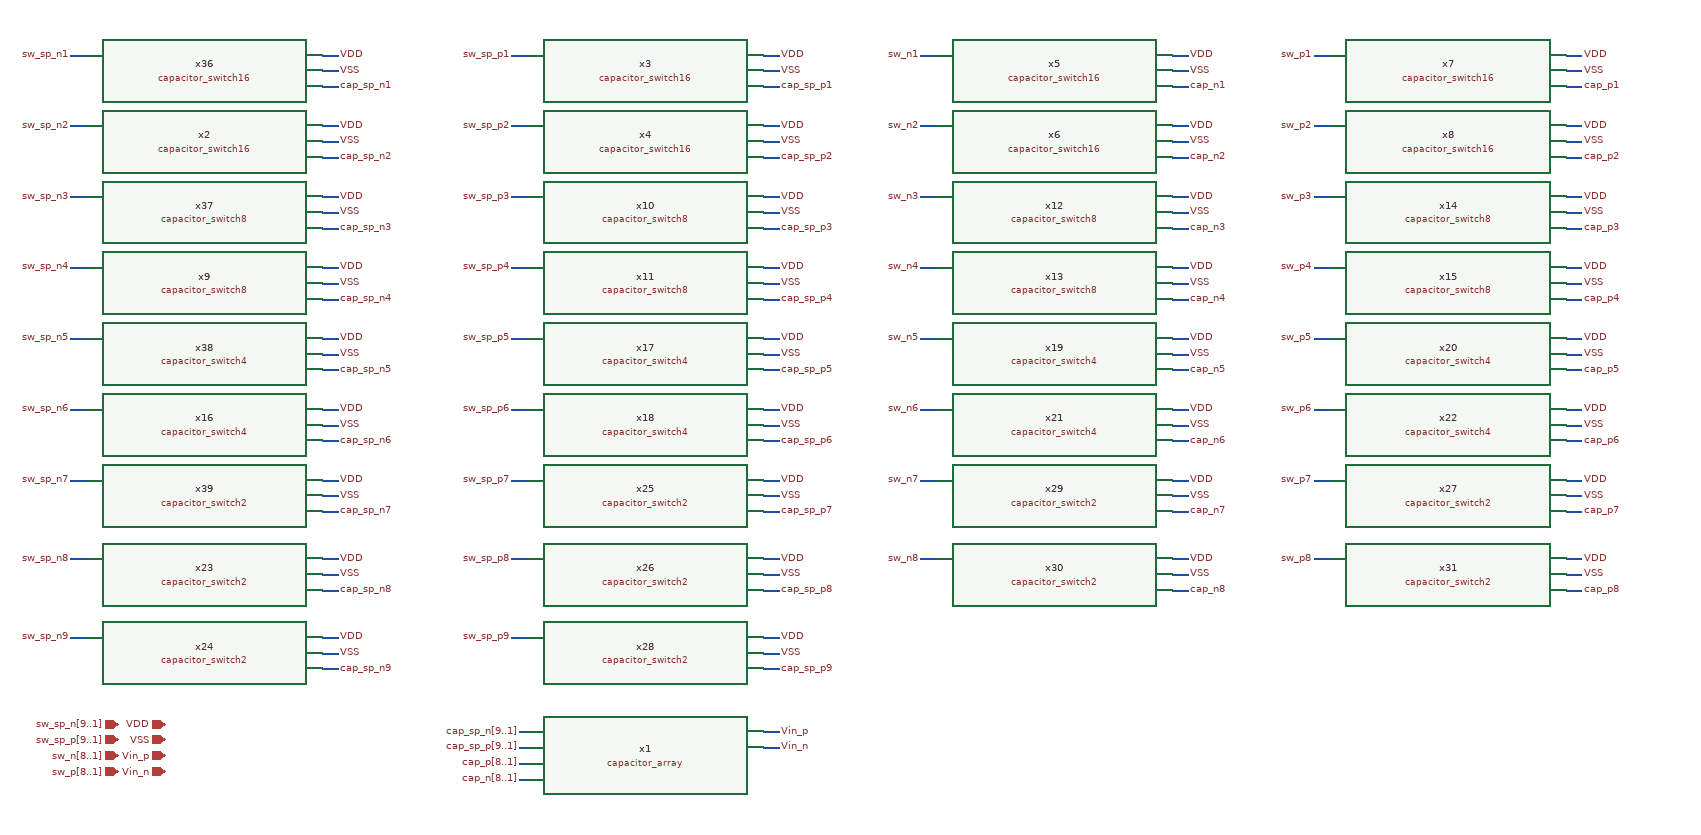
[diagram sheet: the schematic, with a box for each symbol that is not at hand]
v {xschem version=3.1.0 file_version=1.2
}
G {}
K {}
V {}
S {}
E {}
N 690 -110 700 -110 {
lab=cap_sp_n[9..1]}
N 690 -90 700 -90 {
lab=cap_sp_p[9..1]}
N 690 -70 700 -70 {
lab=cap_p[8..1]}
N 690 -50 700 -50 {
lab=cap_n[8..1]}
N 1000 -110 1020 -110 {
lab=Vin_p}
N 1000 -90 1020 -90 {
lab=Vin_n}
N 440 -930 460 -930 {
lab=cap_sp_n1}
N 440 -970 460 -970 {
lab=VDD}
N 440 -950 460 -950 {
lab=VSS}
N 120 -970 140 -970 {
lab=sw_sp_n1}
N 440 -840 460 -840 {
lab=cap_sp_n2}
N 440 -880 460 -880 {
lab=VDD}
N 440 -860 460 -860 {
lab=VSS}
N 120 -880 140 -880 {
lab=sw_sp_n2}
N 440 -750 460 -750 {
lab=cap_sp_n3}
N 440 -790 460 -790 {
lab=VDD}
N 440 -770 460 -770 {
lab=VSS}
N 120 -790 140 -790 {
lab=sw_sp_n3}
N 440 -660 460 -660 {
lab=cap_sp_n4}
N 440 -700 460 -700 {
lab=VDD}
N 440 -680 460 -680 {
lab=VSS}
N 120 -700 140 -700 {
lab=sw_sp_n4}
N 440 -570 460 -570 {
lab=cap_sp_n5}
N 440 -610 460 -610 {
lab=VDD}
N 440 -590 460 -590 {
lab=VSS}
N 120 -610 140 -610 {
lab=sw_sp_n5}
N 440 -480 460 -480 {
lab=cap_sp_n6}
N 440 -520 460 -520 {
lab=VDD}
N 440 -500 460 -500 {
lab=VSS}
N 120 -520 140 -520 {
lab=sw_sp_n6}
N 440 -390 460 -390 {
lab=cap_sp_n7}
N 440 -430 460 -430 {
lab=VDD}
N 440 -410 460 -410 {
lab=VSS}
N 120 -430 140 -430 {
lab=sw_sp_n7}
N 440 -290 460 -290 {
lab=cap_sp_n8}
N 440 -330 460 -330 {
lab=VDD}
N 440 -310 460 -310 {
lab=VSS}
N 120 -330 140 -330 {
lab=sw_sp_n8}
N 440 -190 460 -190 {
lab=cap_sp_n9}
N 440 -230 460 -230 {
lab=VDD}
N 440 -210 460 -210 {
lab=VSS}
N 120 -230 140 -230 {
lab=sw_sp_n9}
N 1000 -930 1020 -930 {
lab=cap_sp_p1}
N 1000 -970 1020 -970 {
lab=VDD}
N 1000 -950 1020 -950 {
lab=VSS}
N 680 -970 700 -970 {
lab=sw_sp_p1}
N 1000 -840 1020 -840 {
lab=cap_sp_p2}
N 1000 -880 1020 -880 {
lab=VDD}
N 1000 -860 1020 -860 {
lab=VSS}
N 680 -880 700 -880 {
lab=sw_sp_p2}
N 1000 -750 1020 -750 {
lab=cap_sp_p3}
N 1000 -790 1020 -790 {
lab=VDD}
N 1000 -770 1020 -770 {
lab=VSS}
N 680 -790 700 -790 {
lab=sw_sp_p3}
N 1000 -660 1020 -660 {
lab=cap_sp_p4}
N 1000 -700 1020 -700 {
lab=VDD}
N 1000 -680 1020 -680 {
lab=VSS}
N 680 -700 700 -700 {
lab=sw_sp_p4}
N 1000 -570 1020 -570 {
lab=cap_sp_p5}
N 1000 -610 1020 -610 {
lab=VDD}
N 1000 -590 1020 -590 {
lab=VSS}
N 680 -610 700 -610 {
lab=sw_sp_p5}
N 1000 -480 1020 -480 {
lab=cap_sp_p6}
N 1000 -520 1020 -520 {
lab=VDD}
N 1000 -500 1020 -500 {
lab=VSS}
N 680 -520 700 -520 {
lab=sw_sp_p6}
N 1000 -390 1020 -390 {
lab=cap_sp_p7}
N 1000 -430 1020 -430 {
lab=VDD}
N 1000 -410 1020 -410 {
lab=VSS}
N 680 -430 700 -430 {
lab=sw_sp_p7}
N 1000 -290 1020 -290 {
lab=cap_sp_p8}
N 1000 -330 1020 -330 {
lab=VDD}
N 1000 -310 1020 -310 {
lab=VSS}
N 680 -330 700 -330 {
lab=sw_sp_p8}
N 1000 -190 1020 -190 {
lab=cap_sp_p9}
N 1000 -230 1020 -230 {
lab=VDD}
N 1000 -210 1020 -210 {
lab=VSS}
N 680 -230 700 -230 {
lab=sw_sp_p9}
N 2020 -930 2040 -930 {
lab=cap_p1}
N 2020 -970 2040 -970 {
lab=VDD}
N 2020 -950 2040 -950 {
lab=VSS}
N 1700 -970 1720 -970 {
lab=sw_p1}
N 2020 -840 2040 -840 {
lab=cap_p2}
N 2020 -880 2040 -880 {
lab=VDD}
N 2020 -860 2040 -860 {
lab=VSS}
N 1700 -880 1720 -880 {
lab=sw_p2}
N 2020 -750 2040 -750 {
lab=cap_p3}
N 2020 -790 2040 -790 {
lab=VDD}
N 2020 -770 2040 -770 {
lab=VSS}
N 1700 -790 1720 -790 {
lab=sw_p3}
N 2020 -660 2040 -660 {
lab=cap_p4}
N 2020 -700 2040 -700 {
lab=VDD}
N 2020 -680 2040 -680 {
lab=VSS}
N 1700 -700 1720 -700 {
lab=sw_p4}
N 2020 -570 2040 -570 {
lab=cap_p5}
N 2020 -610 2040 -610 {
lab=VDD}
N 2020 -590 2040 -590 {
lab=VSS}
N 1700 -610 1720 -610 {
lab=sw_p5}
N 2020 -480 2040 -480 {
lab=cap_p6}
N 2020 -520 2040 -520 {
lab=VDD}
N 2020 -500 2040 -500 {
lab=VSS}
N 1700 -520 1720 -520 {
lab=sw_p6}
N 2020 -390 2040 -390 {
lab=cap_p7}
N 2020 -430 2040 -430 {
lab=VDD}
N 2020 -410 2040 -410 {
lab=VSS}
N 1700 -430 1720 -430 {
lab=sw_p7}
N 2020 -290 2040 -290 {
lab=cap_p8}
N 2020 -330 2040 -330 {
lab=VDD}
N 2020 -310 2040 -310 {
lab=VSS}
N 1700 -330 1720 -330 {
lab=sw_p8}
N 1520 -930 1540 -930 {
lab=cap_n1}
N 1520 -970 1540 -970 {
lab=VDD}
N 1520 -950 1540 -950 {
lab=VSS}
N 1200 -970 1220 -970 {
lab=sw_n1}
N 1520 -840 1540 -840 {
lab=cap_n2}
N 1520 -880 1540 -880 {
lab=VDD}
N 1520 -860 1540 -860 {
lab=VSS}
N 1200 -880 1220 -880 {
lab=sw_n2}
N 1520 -750 1540 -750 {
lab=cap_n3}
N 1520 -790 1540 -790 {
lab=VDD}
N 1520 -770 1540 -770 {
lab=VSS}
N 1200 -790 1220 -790 {
lab=sw_n3}
N 1520 -660 1540 -660 {
lab=cap_n4}
N 1520 -700 1540 -700 {
lab=VDD}
N 1520 -680 1540 -680 {
lab=VSS}
N 1200 -700 1220 -700 {
lab=sw_n4}
N 1520 -570 1540 -570 {
lab=cap_n5}
N 1520 -610 1540 -610 {
lab=VDD}
N 1520 -590 1540 -590 {
lab=VSS}
N 1200 -610 1220 -610 {
lab=sw_n5}
N 1520 -480 1540 -480 {
lab=cap_n6}
N 1520 -520 1540 -520 {
lab=VDD}
N 1520 -500 1540 -500 {
lab=VSS}
N 1200 -520 1220 -520 {
lab=sw_n6}
N 1520 -390 1540 -390 {
lab=cap_n7}
N 1520 -430 1540 -430 {
lab=VDD}
N 1520 -410 1540 -410 {
lab=VSS}
N 1200 -430 1220 -430 {
lab=sw_n7}
N 1520 -290 1540 -290 {
lab=cap_n8}
N 1520 -330 1540 -330 {
lab=VDD}
N 1520 -310 1540 -310 {
lab=VSS}
N 1200 -330 1220 -330 {
lab=sw_n8}
C {devices/title.sym} 160 30 0 0 {name=l1 author="Dr. Aubrey Beal, Dr. Phillip Bailey, Micah Tseng"
}
C {src/capacitor_array/capacitor_array.sym} 850 -80 0 0 {name=x1 unit_cap_w=5 unit_cap_l=5
}
C {devices/iopin.sym} 240 -120 0 0 {name=p1 lab=VDD
}
C {devices/ipin.sym} 180 -120 0 0 {name=p3 lab=sw_sp_n[9..1]
}
C {devices/iopin.sym} 240 -100 0 0 {name=p4 lab=VSS
}
C {devices/iopin.sym} 240 -80 0 0 {name=p5 lab=Vin_p
}
C {devices/iopin.sym} 240 -60 0 0 {name=p6 lab=Vin_n
}
C {devices/ipin.sym} 180 -100 0 0 {name=p2 lab=sw_sp_p[9..1]
}
C {devices/ipin.sym} 180 -80 0 0 {name=p7 lab=sw_n[8..1]
}
C {devices/ipin.sym} 180 -60 0 0 {name=p8 lab=sw_p[8..1]
}
C {devices/lab_pin.sym} 690 -110 0 0 {name=l2 sig_type=std_logic lab=cap_sp_n[9..1]
}
C {devices/lab_pin.sym} 690 -90 0 0 {name=l3 sig_type=std_logic lab=cap_sp_p[9..1]
}
C {devices/lab_pin.sym} 690 -70 0 0 {name=l4 sig_type=std_logic lab=cap_p[8..1]
}
C {devices/lab_pin.sym} 690 -50 0 0 {name=l5 sig_type=std_logic lab=cap_n[8..1]
}
C {devices/lab_pin.sym} 1020 -110 2 0 {name=l6 sig_type=std_logic lab=Vin_p
}
C {devices/lab_pin.sym} 1020 -90 2 0 {name=l7 sig_type=std_logic lab=Vin_n
}
C {devices/lab_pin.sym} 460 -930 2 0 {name=l8 sig_type=std_logic lab=cap_sp_n1
}
C {devices/lab_pin.sym} 460 -970 2 0 {name=l9 sig_type=std_logic lab=VDD
}
C {devices/lab_pin.sym} 460 -950 2 0 {name=l10 sig_type=std_logic lab=VSS
}
C {devices/lab_pin.sym} 120 -970 0 0 {name=l11 sig_type=std_logic lab=sw_sp_n1
}
C {devices/lab_pin.sym} 460 -840 2 0 {name=l12 sig_type=std_logic lab=cap_sp_n2
}
C {devices/lab_pin.sym} 460 -880 2 0 {name=l13 sig_type=std_logic lab=VDD
}
C {devices/lab_pin.sym} 460 -860 2 0 {name=l14 sig_type=std_logic lab=VSS
}
C {devices/lab_pin.sym} 120 -880 0 0 {name=l15 sig_type=std_logic lab=sw_sp_n2
}
C {devices/lab_pin.sym} 460 -750 2 0 {name=l16 sig_type=std_logic lab=cap_sp_n3
}
C {devices/lab_pin.sym} 460 -790 2 0 {name=l17 sig_type=std_logic lab=VDD
}
C {devices/lab_pin.sym} 460 -770 2 0 {name=l18 sig_type=std_logic lab=VSS
}
C {devices/lab_pin.sym} 120 -790 0 0 {name=l19 sig_type=std_logic lab=sw_sp_n3
}
C {devices/lab_pin.sym} 460 -660 2 0 {name=l20 sig_type=std_logic lab=cap_sp_n4
}
C {devices/lab_pin.sym} 460 -700 2 0 {name=l21 sig_type=std_logic lab=VDD
}
C {devices/lab_pin.sym} 460 -680 2 0 {name=l22 sig_type=std_logic lab=VSS
}
C {devices/lab_pin.sym} 120 -700 0 0 {name=l23 sig_type=std_logic lab=sw_sp_n4
}
C {devices/lab_pin.sym} 460 -570 2 0 {name=l24 sig_type=std_logic lab=cap_sp_n5
}
C {devices/lab_pin.sym} 460 -610 2 0 {name=l25 sig_type=std_logic lab=VDD
}
C {devices/lab_pin.sym} 460 -590 2 0 {name=l26 sig_type=std_logic lab=VSS
}
C {devices/lab_pin.sym} 120 -610 0 0 {name=l27 sig_type=std_logic lab=sw_sp_n5
}
C {devices/lab_pin.sym} 460 -480 2 0 {name=l28 sig_type=std_logic lab=cap_sp_n6
}
C {devices/lab_pin.sym} 460 -520 2 0 {name=l29 sig_type=std_logic lab=VDD
}
C {devices/lab_pin.sym} 460 -500 2 0 {name=l30 sig_type=std_logic lab=VSS
}
C {devices/lab_pin.sym} 120 -520 0 0 {name=l31 sig_type=std_logic lab=sw_sp_n6
}
C {devices/lab_pin.sym} 460 -390 2 0 {name=l32 sig_type=std_logic lab=cap_sp_n7
}
C {devices/lab_pin.sym} 460 -430 2 0 {name=l33 sig_type=std_logic lab=VDD
}
C {devices/lab_pin.sym} 460 -410 2 0 {name=l34 sig_type=std_logic lab=VSS
}
C {devices/lab_pin.sym} 120 -430 0 0 {name=l35 sig_type=std_logic lab=sw_sp_n7
}
C {devices/lab_pin.sym} 460 -290 2 0 {name=l36 sig_type=std_logic lab=cap_sp_n8
}
C {devices/lab_pin.sym} 460 -330 2 0 {name=l37 sig_type=std_logic lab=VDD
}
C {devices/lab_pin.sym} 460 -310 2 0 {name=l38 sig_type=std_logic lab=VSS
}
C {devices/lab_pin.sym} 120 -330 0 0 {name=l39 sig_type=std_logic lab=sw_sp_n8
}
C {devices/lab_pin.sym} 460 -190 2 0 {name=l40 sig_type=std_logic lab=cap_sp_n9
}
C {devices/lab_pin.sym} 460 -230 2 0 {name=l41 sig_type=std_logic lab=VDD
}
C {devices/lab_pin.sym} 460 -210 2 0 {name=l42 sig_type=std_logic lab=VSS
}
C {devices/lab_pin.sym} 120 -230 0 0 {name=l43 sig_type=std_logic lab=sw_sp_n9
}
C {devices/lab_pin.sym} 1020 -930 2 0 {name=l44 sig_type=std_logic lab=cap_sp_p1
}
C {devices/lab_pin.sym} 1020 -970 2 0 {name=l45 sig_type=std_logic lab=VDD
}
C {devices/lab_pin.sym} 1020 -950 2 0 {name=l46 sig_type=std_logic lab=VSS
}
C {devices/lab_pin.sym} 680 -970 0 0 {name=l47 sig_type=std_logic lab=sw_sp_p1
}
C {devices/lab_pin.sym} 1020 -840 2 0 {name=l48 sig_type=std_logic lab=cap_sp_p2
}
C {devices/lab_pin.sym} 1020 -880 2 0 {name=l49 sig_type=std_logic lab=VDD
}
C {devices/lab_pin.sym} 1020 -860 2 0 {name=l50 sig_type=std_logic lab=VSS
}
C {devices/lab_pin.sym} 680 -880 0 0 {name=l51 sig_type=std_logic lab=sw_sp_p2
}
C {devices/lab_pin.sym} 1020 -750 2 0 {name=l52 sig_type=std_logic lab=cap_sp_p3
}
C {devices/lab_pin.sym} 1020 -790 2 0 {name=l53 sig_type=std_logic lab=VDD
}
C {devices/lab_pin.sym} 1020 -770 2 0 {name=l54 sig_type=std_logic lab=VSS
}
C {devices/lab_pin.sym} 680 -790 0 0 {name=l55 sig_type=std_logic lab=sw_sp_p3
}
C {devices/lab_pin.sym} 1020 -660 2 0 {name=l56 sig_type=std_logic lab=cap_sp_p4
}
C {devices/lab_pin.sym} 1020 -700 2 0 {name=l57 sig_type=std_logic lab=VDD
}
C {devices/lab_pin.sym} 1020 -680 2 0 {name=l58 sig_type=std_logic lab=VSS
}
C {devices/lab_pin.sym} 680 -700 0 0 {name=l59 sig_type=std_logic lab=sw_sp_p4
}
C {devices/lab_pin.sym} 1020 -570 2 0 {name=l60 sig_type=std_logic lab=cap_sp_p5
}
C {devices/lab_pin.sym} 1020 -610 2 0 {name=l61 sig_type=std_logic lab=VDD
}
C {devices/lab_pin.sym} 1020 -590 2 0 {name=l62 sig_type=std_logic lab=VSS
}
C {devices/lab_pin.sym} 680 -610 0 0 {name=l63 sig_type=std_logic lab=sw_sp_p5
}
C {devices/lab_pin.sym} 1020 -480 2 0 {name=l64 sig_type=std_logic lab=cap_sp_p6
}
C {devices/lab_pin.sym} 1020 -520 2 0 {name=l65 sig_type=std_logic lab=VDD
}
C {devices/lab_pin.sym} 1020 -500 2 0 {name=l66 sig_type=std_logic lab=VSS
}
C {devices/lab_pin.sym} 680 -520 0 0 {name=l67 sig_type=std_logic lab=sw_sp_p6
}
C {devices/lab_pin.sym} 1020 -390 2 0 {name=l68 sig_type=std_logic lab=cap_sp_p7
}
C {devices/lab_pin.sym} 1020 -430 2 0 {name=l69 sig_type=std_logic lab=VDD
}
C {devices/lab_pin.sym} 1020 -410 2 0 {name=l70 sig_type=std_logic lab=VSS
}
C {devices/lab_pin.sym} 680 -430 0 0 {name=l71 sig_type=std_logic lab=sw_sp_p7
}
C {devices/lab_pin.sym} 1020 -290 2 0 {name=l72 sig_type=std_logic lab=cap_sp_p8
}
C {devices/lab_pin.sym} 1020 -330 2 0 {name=l73 sig_type=std_logic lab=VDD
}
C {devices/lab_pin.sym} 1020 -310 2 0 {name=l74 sig_type=std_logic lab=VSS
}
C {devices/lab_pin.sym} 680 -330 0 0 {name=l75 sig_type=std_logic lab=sw_sp_p8
}
C {devices/lab_pin.sym} 1020 -190 2 0 {name=l76 sig_type=std_logic lab=cap_sp_p9
}
C {devices/lab_pin.sym} 1020 -230 2 0 {name=l77 sig_type=std_logic lab=VDD
}
C {devices/lab_pin.sym} 1020 -210 2 0 {name=l78 sig_type=std_logic lab=VSS
}
C {devices/lab_pin.sym} 680 -230 0 0 {name=l79 sig_type=std_logic lab=sw_sp_p9
}
C {devices/lab_pin.sym} 2040 -930 2 0 {name=l80 sig_type=std_logic lab=cap_p1
}
C {devices/lab_pin.sym} 2040 -970 2 0 {name=l81 sig_type=std_logic lab=VDD
}
C {devices/lab_pin.sym} 2040 -950 2 0 {name=l82 sig_type=std_logic lab=VSS
}
C {devices/lab_pin.sym} 1700 -970 0 0 {name=l83 sig_type=std_logic lab=sw_p1
}
C {devices/lab_pin.sym} 2040 -840 2 0 {name=l84 sig_type=std_logic lab=cap_p2
}
C {devices/lab_pin.sym} 2040 -880 2 0 {name=l85 sig_type=std_logic lab=VDD
}
C {devices/lab_pin.sym} 2040 -860 2 0 {name=l86 sig_type=std_logic lab=VSS
}
C {devices/lab_pin.sym} 1700 -880 0 0 {name=l87 sig_type=std_logic lab=sw_p2
}
C {devices/lab_pin.sym} 2040 -750 2 0 {name=l88 sig_type=std_logic lab=cap_p3
}
C {devices/lab_pin.sym} 2040 -790 2 0 {name=l89 sig_type=std_logic lab=VDD
}
C {devices/lab_pin.sym} 2040 -770 2 0 {name=l90 sig_type=std_logic lab=VSS
}
C {devices/lab_pin.sym} 1700 -790 0 0 {name=l91 sig_type=std_logic lab=sw_p3
}
C {devices/lab_pin.sym} 2040 -660 2 0 {name=l92 sig_type=std_logic lab=cap_p4
}
C {devices/lab_pin.sym} 2040 -700 2 0 {name=l93 sig_type=std_logic lab=VDD
}
C {devices/lab_pin.sym} 2040 -680 2 0 {name=l94 sig_type=std_logic lab=VSS
}
C {devices/lab_pin.sym} 1700 -700 0 0 {name=l95 sig_type=std_logic lab=sw_p4
}
C {devices/lab_pin.sym} 2040 -570 2 0 {name=l96 sig_type=std_logic lab=cap_p5
}
C {devices/lab_pin.sym} 2040 -610 2 0 {name=l97 sig_type=std_logic lab=VDD
}
C {devices/lab_pin.sym} 2040 -590 2 0 {name=l98 sig_type=std_logic lab=VSS
}
C {devices/lab_pin.sym} 1700 -610 0 0 {name=l99 sig_type=std_logic lab=sw_p5
}
C {devices/lab_pin.sym} 2040 -480 2 0 {name=l100 sig_type=std_logic lab=cap_p6
}
C {devices/lab_pin.sym} 2040 -520 2 0 {name=l101 sig_type=std_logic lab=VDD
}
C {devices/lab_pin.sym} 2040 -500 2 0 {name=l102 sig_type=std_logic lab=VSS
}
C {devices/lab_pin.sym} 1700 -520 0 0 {name=l103 sig_type=std_logic lab=sw_p6
}
C {devices/lab_pin.sym} 2040 -390 2 0 {name=l104 sig_type=std_logic lab=cap_p7
}
C {devices/lab_pin.sym} 2040 -430 2 0 {name=l105 sig_type=std_logic lab=VDD
}
C {devices/lab_pin.sym} 2040 -410 2 0 {name=l106 sig_type=std_logic lab=VSS
}
C {devices/lab_pin.sym} 1700 -430 0 0 {name=l107 sig_type=std_logic lab=sw_p7
}
C {devices/lab_pin.sym} 2040 -290 2 0 {name=l108 sig_type=std_logic lab=cap_p8
}
C {devices/lab_pin.sym} 2040 -330 2 0 {name=l109 sig_type=std_logic lab=VDD
}
C {devices/lab_pin.sym} 2040 -310 2 0 {name=l110 sig_type=std_logic lab=VSS
}
C {devices/lab_pin.sym} 1700 -330 0 0 {name=l111 sig_type=std_logic lab=sw_p8
}
C {devices/lab_pin.sym} 1540 -930 2 0 {name=l112 sig_type=std_logic lab=cap_n1
}
C {devices/lab_pin.sym} 1540 -970 2 0 {name=l113 sig_type=std_logic lab=VDD
}
C {devices/lab_pin.sym} 1540 -950 2 0 {name=l114 sig_type=std_logic lab=VSS
}
C {devices/lab_pin.sym} 1200 -970 0 0 {name=l115 sig_type=std_logic lab=sw_n1
}
C {devices/lab_pin.sym} 1540 -840 2 0 {name=l116 sig_type=std_logic lab=cap_n2
}
C {devices/lab_pin.sym} 1540 -880 2 0 {name=l117 sig_type=std_logic lab=VDD
}
C {devices/lab_pin.sym} 1540 -860 2 0 {name=l118 sig_type=std_logic lab=VSS
}
C {devices/lab_pin.sym} 1200 -880 0 0 {name=l119 sig_type=std_logic lab=sw_n2
}
C {devices/lab_pin.sym} 1540 -750 2 0 {name=l120 sig_type=std_logic lab=cap_n3
}
C {devices/lab_pin.sym} 1540 -790 2 0 {name=l121 sig_type=std_logic lab=VDD
}
C {devices/lab_pin.sym} 1540 -770 2 0 {name=l122 sig_type=std_logic lab=VSS
}
C {devices/lab_pin.sym} 1200 -790 0 0 {name=l123 sig_type=std_logic lab=sw_n3
}
C {devices/lab_pin.sym} 1540 -660 2 0 {name=l124 sig_type=std_logic lab=cap_n4
}
C {devices/lab_pin.sym} 1540 -700 2 0 {name=l125 sig_type=std_logic lab=VDD
}
C {devices/lab_pin.sym} 1540 -680 2 0 {name=l126 sig_type=std_logic lab=VSS
}
C {devices/lab_pin.sym} 1200 -700 0 0 {name=l127 sig_type=std_logic lab=sw_n4
}
C {devices/lab_pin.sym} 1540 -570 2 0 {name=l128 sig_type=std_logic lab=cap_n5
}
C {devices/lab_pin.sym} 1540 -610 2 0 {name=l129 sig_type=std_logic lab=VDD
}
C {devices/lab_pin.sym} 1540 -590 2 0 {name=l130 sig_type=std_logic lab=VSS
}
C {devices/lab_pin.sym} 1200 -610 0 0 {name=l131 sig_type=std_logic lab=sw_n5
}
C {devices/lab_pin.sym} 1540 -480 2 0 {name=l132 sig_type=std_logic lab=cap_n6
}
C {devices/lab_pin.sym} 1540 -520 2 0 {name=l133 sig_type=std_logic lab=VDD
}
C {devices/lab_pin.sym} 1540 -500 2 0 {name=l134 sig_type=std_logic lab=VSS
}
C {devices/lab_pin.sym} 1200 -520 0 0 {name=l135 sig_type=std_logic lab=sw_n6
}
C {devices/lab_pin.sym} 1540 -390 2 0 {name=l136 sig_type=std_logic lab=cap_n7
}
C {devices/lab_pin.sym} 1540 -430 2 0 {name=l137 sig_type=std_logic lab=VDD
}
C {devices/lab_pin.sym} 1540 -410 2 0 {name=l138 sig_type=std_logic lab=VSS
}
C {devices/lab_pin.sym} 1200 -430 0 0 {name=l139 sig_type=std_logic lab=sw_n7
}
C {devices/lab_pin.sym} 1540 -290 2 0 {name=l140 sig_type=std_logic lab=cap_n8
}
C {devices/lab_pin.sym} 1540 -330 2 0 {name=l141 sig_type=std_logic lab=VDD
}
C {devices/lab_pin.sym} 1540 -310 2 0 {name=l142 sig_type=std_logic lab=VSS
}
C {devices/lab_pin.sym} 1200 -330 0 0 {name=l143 sig_type=std_logic lab=sw_n8
}
C {src/capacitor_switch16/capacitor_switch16.sym} 290 -950 0 0 {name=x36}
C {src/capacitor_switch8/capacitor_switch8.sym} 290 -770 0 0 {name=x37}
C {src/capacitor_switch4/capacitor_switch4.sym} 290 -590 0 0 {name=x38}
C {src/capacitor_switch2/capacitor_switch2.sym} 290 -410 0 0 {name=x39}
C {src/capacitor_switch16/capacitor_switch16.sym} 290 -860 0 0 {name=x2}
C {src/capacitor_switch16/capacitor_switch16.sym} 850 -950 0 0 {name=x3}
C {src/capacitor_switch16/capacitor_switch16.sym} 850 -860 0 0 {name=x4}
C {src/capacitor_switch16/capacitor_switch16.sym} 1370 -950 0 0 {name=x5}
C {src/capacitor_switch16/capacitor_switch16.sym} 1370 -860 0 0 {name=x6}
C {src/capacitor_switch16/capacitor_switch16.sym} 1870 -950 0 0 {name=x7}
C {src/capacitor_switch16/capacitor_switch16.sym} 1870 -860 0 0 {name=x8}
C {src/capacitor_switch8/capacitor_switch8.sym} 290 -680 0 0 {name=x9}
C {src/capacitor_switch8/capacitor_switch8.sym} 850 -770 0 0 {name=x10}
C {src/capacitor_switch8/capacitor_switch8.sym} 850 -680 0 0 {name=x11}
C {src/capacitor_switch8/capacitor_switch8.sym} 1370 -770 0 0 {name=x12}
C {src/capacitor_switch8/capacitor_switch8.sym} 1370 -680 0 0 {name=x13}
C {src/capacitor_switch8/capacitor_switch8.sym} 1870 -770 0 0 {name=x14}
C {src/capacitor_switch8/capacitor_switch8.sym} 1870 -680 0 0 {name=x15}
C {src/capacitor_switch4/capacitor_switch4.sym} 290 -500 0 0 {name=x16}
C {src/capacitor_switch4/capacitor_switch4.sym} 850 -590 0 0 {name=x17}
C {src/capacitor_switch4/capacitor_switch4.sym} 850 -500 0 0 {name=x18}
C {src/capacitor_switch4/capacitor_switch4.sym} 1370 -590 0 0 {name=x19}
C {src/capacitor_switch4/capacitor_switch4.sym} 1870 -590 0 0 {name=x20}
C {src/capacitor_switch4/capacitor_switch4.sym} 1370 -500 0 0 {name=x21}
C {src/capacitor_switch4/capacitor_switch4.sym} 1870 -500 0 0 {name=x22}
C {src/capacitor_switch2/capacitor_switch2.sym} 290 -310 0 0 {name=x23}
C {src/capacitor_switch2/capacitor_switch2.sym} 290 -210 0 0 {name=x24}
C {src/capacitor_switch2/capacitor_switch2.sym} 850 -410 0 0 {name=x25}
C {src/capacitor_switch2/capacitor_switch2.sym} 850 -310 0 0 {name=x26}
C {src/capacitor_switch2/capacitor_switch2.sym} 850 -210 0 0 {name=x28}
C {src/capacitor_switch2/capacitor_switch2.sym} 1370 -410 0 0 {name=x29}
C {src/capacitor_switch2/capacitor_switch2.sym} 1370 -310 0 0 {name=x30}
C {src/capacitor_switch2/capacitor_switch2.sym} 1870 -410 0 0 {name=x27}
C {src/capacitor_switch2/capacitor_switch2.sym} 1870 -310 0 0 {name=x31}
